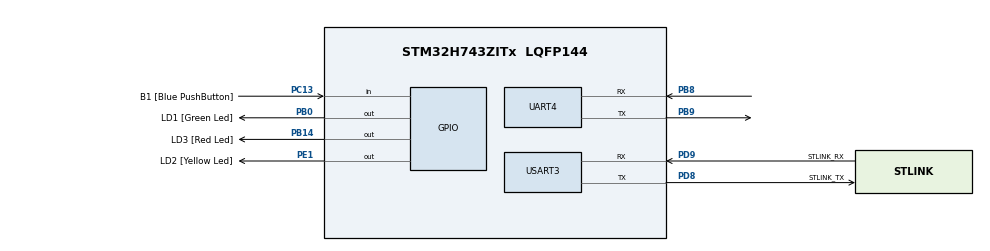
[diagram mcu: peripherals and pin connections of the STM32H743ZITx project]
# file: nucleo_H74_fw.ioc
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Mcu.Family=STM32H7
Mcu.Name=STM32H743ZITx
Mcu.Package=LQFP144
NVIC.PriorityGroup=NVIC_PRIORITYGROUP_4
NVIC.TIM2_IRQn=true\:12\:0\:true\:false\:true\:true\:true\:true
NVIC.TIM3_IRQn=true\:13\:0\:true\:false\:true\:true\:true\:true
NVIC.UART4_IRQn=true\:15\:0\:true\:false\:true\:true\:true\:true
NVIC.USART3_IRQn=true\:14\:0\:true\:false\:true\:true\:true\:true
PA13\ (JTMS/SWDIO).Mode=Serial_Wire
PA13\ (JTMS/SWDIO).Signal=DEBUG_JTMS-SWDIO
PA14\ (JTCK/SWCLK).Mode=Serial_Wire
PA14\ (JTCK/SWCLK).Signal=DEBUG_JTCK-SWCLK
PB0.GPIO_Label=LD1 [Green Led]
PB0.Signal=GPIO_Output
PB14.GPIO_Label=LD3 [Red Led]
PB14.Signal=GPIO_Output
PB8.GPIO_PuPd=GPIO_PULLUP
PB8.Mode=Asynchronous
PB8.Signal=UART4_RX
PB9.GPIO_PuPd=GPIO_PULLUP
PB9.Mode=Asynchronous
PB9.Signal=UART4_TX
PC13.GPIO_Label=B1 [Blue PushButton]
PC13.Signal=GPIO_Input
PC14-OSC32_IN\ (OSC32_IN).Mode=LSE-External-Oscillator
PC14-OSC32_IN\ (OSC32_IN).Signal=RCC_OSC32_IN
PC15-OSC32_OUT\ (OSC32_OUT).Mode=LSE-External-Oscillator
PC15-OSC32_OUT\ (OSC32_OUT).Signal=RCC_OSC32_OUT
PD8.GPIO_Label=STLINK_TX
PD8.Mode=Asynchronous
PD8.Signal=USART3_TX
PD9.GPIO_Label=STLINK_RX
PD9.Mode=Asynchronous
PD9.Signal=USART3_RX
PE1.GPIO_Label=LD2 [Yellow Led]
PE1.Signal=GPIO_Output
PH0-OSC_IN\ (PH0).Mode=HSE-External-Clock-Source
PH0-OSC_IN\ (PH0).Signal=RCC_OSC_IN
ProjectManager.HeapSize=0x200
ProjectManager.StackSize=0x400
ProjectManager.TargetToolchain=MDK-ARM V5
RCC.ADCFreq_Value=16125000
RCC.APB1Freq_Value=32000000
RCC.APB2Freq_Value=64000000
RCC.APB3Freq_Value=64000000
RCC.APB4Freq_Value=64000000
RCC.CortexFreq_Value=64000000
RCC.D2PPRE1=RCC_APB1_DIV2
RCC.DIVM1=1
RCC.DIVN1=24
RCC.HCLKFreq_Value=64000000
RCC.HSE_VALUE=8000000
RCC.PLLSourceVirtual=RCC_PLLSOURCE_HSE
RCC.SYSCLKFreq_VALUE=64000000
RCC.USBFreq_Value=96000000
TIM2.Prescaler=63
TIM3.Period=9999
TIM3.Prescaler=63
USART3.VirtualMode-Asynchronous=VM_ASYNC
VP_TIM2_VS_ClockSourceINT.Mode=Internal
VP_TIM3_VS_ClockSourceINT.Mode=Internal
board=custom

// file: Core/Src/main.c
/* USER CODE BEGIN Header */
/**
  ******************************************************************************
  * @file           : main.c
  * @brief          : Main program body
  ******************************************************************************
  * @attention
  *
  * <h2><center>&copy; Copyright (c) 2021 STMicroelectronics.
  * All rights reserved.</center></h2>
  *
  * This software component is licensed by ST under BSD 3-Clause license,
  * the "License"; You may not use this file except in compliance with the
  * License. You may obtain a copy of the License at:
  *                        opensource.org/licenses/BSD-3-Clause
  *
  ******************************************************************************
  */
/* USER CODE END Header */
#include "main.h"

/* USER CODE BEGIN Includes */
int user_main(void);
/* USER CODE END Includes */

TIM_HandleTypeDef htim2;
TIM_HandleTypeDef htim3;

UART_HandleTypeDef huart4;
UART_HandleTypeDef huart3;

void SystemClock_Config(void);
static void MX_GPIO_Init(void);
static void MX_USART3_UART_Init(void);
static void MX_TIM2_Init(void);
static void MX_TIM3_Init(void);
static void MX_UART4_Init(void);

int main(void)
{

  /* MCU Configuration--------------------------------------------------------*/

  /* Reset of all peripherals, Initializes the Flash interface and the Systick. */
  HAL_Init();

  /* Configure the system clock */
  SystemClock_Config();

  /* Initialize all configured peripherals */
  MX_GPIO_Init();
  MX_USART3_UART_Init();
  MX_TIM2_Init();
  MX_TIM3_Init();
  MX_UART4_Init();
  /* USER CODE BEGIN 2 */
  user_main();
  /* USER CODE END 2 */

  /* Infinite loop */
  while (1)
  {

  }
}

void SystemClock_Config(void)
{
  RCC_OscInitTypeDef RCC_OscInitStruct = {0};
  RCC_ClkInitTypeDef RCC_ClkInitStruct = {0};

  /** Supply configuration update enable
  */
  HAL_PWREx_ConfigSupply(PWR_LDO_SUPPLY);
  /** Configure the main internal regulator output voltage
  */
  __HAL_PWR_VOLTAGESCALING_CONFIG(PWR_REGULATOR_VOLTAGE_SCALE2);

  while(!__HAL_PWR_GET_FLAG(PWR_FLAG_VOSRDY)) {}
  /** Initializes the RCC Oscillators according to the specified parameters
  * in the RCC_OscInitTypeDef structure.
  */
  RCC_OscInitStruct.OscillatorType = RCC_OSCILLATORTYPE_HSI;
  RCC_OscInitStruct.HSIState = RCC_HSI_DIV1;
  RCC_OscInitStruct.HSICalibrationValue = RCC_HSICALIBRATION_DEFAULT;
  RCC_OscInitStruct.PLL.PLLState = RCC_PLL_NONE;
  if (HAL_RCC_OscConfig(&RCC_OscInitStruct) != HAL_OK)
  {
    Error_Handler();
  }
  /** Initializes the CPU, AHB and APB buses clocks
  */
  RCC_ClkInitStruct.ClockType = RCC_CLOCKTYPE_HCLK|RCC_CLOCKTYPE_SYSCLK
                              |RCC_CLOCKTYPE_PCLK1|RCC_CLOCKTYPE_PCLK2
                              |RCC_CLOCKTYPE_D3PCLK1|RCC_CLOCKTYPE_D1PCLK1;
  RCC_ClkInitStruct.SYSCLKSource = RCC_SYSCLKSOURCE_HSI;
  RCC_ClkInitStruct.SYSCLKDivider = RCC_SYSCLK_DIV1;
  RCC_ClkInitStruct.AHBCLKDivider = RCC_HCLK_DIV1;
  RCC_ClkInitStruct.APB3CLKDivider = RCC_APB3_DIV1;
  RCC_ClkInitStruct.APB1CLKDivider = RCC_APB1_DIV1;
  RCC_ClkInitStruct.APB2CLKDivider = RCC_APB2_DIV1;
  RCC_ClkInitStruct.APB4CLKDivider = RCC_APB4_DIV1;

  if (HAL_RCC_ClockConfig(&RCC_ClkInitStruct, FLASH_LATENCY_1) != HAL_OK)
  {
    Error_Handler();
  }
}

static void MX_TIM2_Init(void)
{

  TIM_ClockConfigTypeDef sClockSourceConfig = {0};
  TIM_MasterConfigTypeDef sMasterConfig = {0};

  htim2.Instance = TIM2;
  htim2.Init.Prescaler = 63;
  htim2.Init.CounterMode = TIM_COUNTERMODE_UP;
  htim2.Init.Period = 4294967295;
  htim2.Init.ClockDivision = TIM_CLOCKDIVISION_DIV1;
  htim2.Init.AutoReloadPreload = TIM_AUTORELOAD_PRELOAD_DISABLE;
  if (HAL_TIM_Base_Init(&htim2) != HAL_OK)
  {
    Error_Handler();
  }
  sClockSourceConfig.ClockSource = TIM_CLOCKSOURCE_INTERNAL;
  if (HAL_TIM_ConfigClockSource(&htim2, &sClockSourceConfig) != HAL_OK)
  {
    Error_Handler();
  }
  sMasterConfig.MasterOutputTrigger = TIM_TRGO_RESET;
  sMasterConfig.MasterSlaveMode = TIM_MASTERSLAVEMODE_DISABLE;
  if (HAL_TIMEx_MasterConfigSynchronization(&htim2, &sMasterConfig) != HAL_OK)
  {
    Error_Handler();
  }

}

static void MX_TIM3_Init(void)
{

  TIM_ClockConfigTypeDef sClockSourceConfig = {0};
  TIM_MasterConfigTypeDef sMasterConfig = {0};

  htim3.Instance = TIM3;
  htim3.Init.Prescaler = 63;
  htim3.Init.CounterMode = TIM_COUNTERMODE_UP;
  htim3.Init.Period = 9999;
  htim3.Init.ClockDivision = TIM_CLOCKDIVISION_DIV1;
  htim3.Init.AutoReloadPreload = TIM_AUTORELOAD_PRELOAD_DISABLE;
  if (HAL_TIM_Base_Init(&htim3) != HAL_OK)
  {
    Error_Handler();
  }
  sClockSourceConfig.ClockSource = TIM_CLOCKSOURCE_INTERNAL;
  if (HAL_TIM_ConfigClockSource(&htim3, &sClockSourceConfig) != HAL_OK)
  {
    Error_Handler();
  }
  sMasterConfig.MasterOutputTrigger = TIM_TRGO_RESET;
  sMasterConfig.MasterSlaveMode = TIM_MASTERSLAVEMODE_DISABLE;
  if (HAL_TIMEx_MasterConfigSynchronization(&htim3, &sMasterConfig) != HAL_OK)
  {
    Error_Handler();
  }

}

static void MX_UART4_Init(void)
{

  huart4.Instance = UART4;
  huart4.Init.BaudRate = 115200;
  huart4.Init.WordLength = UART_WORDLENGTH_8B;
  huart4.Init.StopBits = UART_STOPBITS_1;
  huart4.Init.Parity = UART_PARITY_NONE;
  huart4.Init.Mode = UART_MODE_TX_RX;
  huart4.Init.HwFlowCtl = UART_HWCONTROL_NONE;
  huart4.Init.OverSampling = UART_OVERSAMPLING_16;
  huart4.Init.OneBitSampling = UART_ONE_BIT_SAMPLE_DISABLE;
  huart4.Init.ClockPrescaler = UART_PRESCALER_DIV1;
  huart4.AdvancedInit.AdvFeatureInit = UART_ADVFEATURE_NO_INIT;
  if (HAL_UART_Init(&huart4) != HAL_OK)
  {
    Error_Handler();
  }
  if (HAL_UARTEx_SetTxFifoThreshold(&huart4, UART_TXFIFO_THRESHOLD_1_8) != HAL_OK)
  {
    Error_Handler();
  }
  if (HAL_UARTEx_SetRxFifoThreshold(&huart4, UART_RXFIFO_THRESHOLD_1_8) != HAL_OK)
  {
    Error_Handler();
  }
  if (HAL_UARTEx_DisableFifoMode(&huart4) != HAL_OK)
  {
    Error_Handler();
  }

}

static void MX_USART3_UART_Init(void)
{

  huart3.Instance = USART3;
  huart3.Init.BaudRate = 115200;
  huart3.Init.WordLength = UART_WORDLENGTH_8B;
  huart3.Init.StopBits = UART_STOPBITS_1;
  huart3.Init.Parity = UART_PARITY_NONE;
  huart3.Init.Mode = UART_MODE_TX_RX;
  huart3.Init.HwFlowCtl = UART_HWCONTROL_NONE;
  huart3.Init.OverSampling = UART_OVERSAMPLING_16;
  huart3.Init.OneBitSampling = UART_ONE_BIT_SAMPLE_DISABLE;
  huart3.Init.ClockPrescaler = UART_PRESCALER_DIV1;
  huart3.AdvancedInit.AdvFeatureInit = UART_ADVFEATURE_NO_INIT;
  if (HAL_UART_Init(&huart3) != HAL_OK)
  {
    Error_Handler();
  }
  if (HAL_UARTEx_SetTxFifoThreshold(&huart3, UART_TXFIFO_THRESHOLD_1_8) != HAL_OK)
  {
    Error_Handler();
  }
  if (HAL_UARTEx_SetRxFifoThreshold(&huart3, UART_RXFIFO_THRESHOLD_1_8) != HAL_OK)
  {
    Error_Handler();
  }
  if (HAL_UARTEx_DisableFifoMode(&huart3) != HAL_OK)
  {
    Error_Handler();
  }

}

static void MX_GPIO_Init(void)
{
  GPIO_InitTypeDef GPIO_InitStruct = {0};

  /* GPIO Ports Clock Enable */
  __HAL_RCC_GPIOC_CLK_ENABLE();
  __HAL_RCC_GPIOH_CLK_ENABLE();
  __HAL_RCC_GPIOB_CLK_ENABLE();
  __HAL_RCC_GPIOD_CLK_ENABLE();
  __HAL_RCC_GPIOA_CLK_ENABLE();
  __HAL_RCC_GPIOE_CLK_ENABLE();

  /*Configure GPIO pin Output Level */
  HAL_GPIO_WritePin(GPIOB, LD1_Pin|LD3_Pin, GPIO_PIN_RESET);

  /*Configure GPIO pin Output Level */
  HAL_GPIO_WritePin(LD2_GPIO_Port, LD2_Pin, GPIO_PIN_RESET);

  /*Configure GPIO pin : B1_Pin */
  GPIO_InitStruct.Pin = B1_Pin;
  GPIO_InitStruct.Mode = GPIO_MODE_INPUT;
  GPIO_InitStruct.Pull = GPIO_NOPULL;
  HAL_GPIO_Init(B1_GPIO_Port, &GPIO_InitStruct);

  /*Configure GPIO pins : LD1_Pin LD3_Pin */
  GPIO_InitStruct.Pin = LD1_Pin|LD3_Pin;
  GPIO_InitStruct.Mode = GPIO_MODE_OUTPUT_PP;
  GPIO_InitStruct.Pull = GPIO_NOPULL;
  GPIO_InitStruct.Speed = GPIO_SPEED_FREQ_LOW;
  HAL_GPIO_Init(GPIOB, &GPIO_InitStruct);

  /*Configure GPIO pin : LD2_Pin */
  GPIO_InitStruct.Pin = LD2_Pin;
  GPIO_InitStruct.Mode = GPIO_MODE_OUTPUT_PP;
  GPIO_InitStruct.Pull = GPIO_NOPULL;
  GPIO_InitStruct.Speed = GPIO_SPEED_FREQ_LOW;
  HAL_GPIO_Init(LD2_GPIO_Port, &GPIO_InitStruct);

}

void Error_Handler(void)
{
  __disable_irq();
  while (1)
  {
  }
}

/************************ (C) COPYRIGHT STMicroelectronics *****END OF FILE****/
